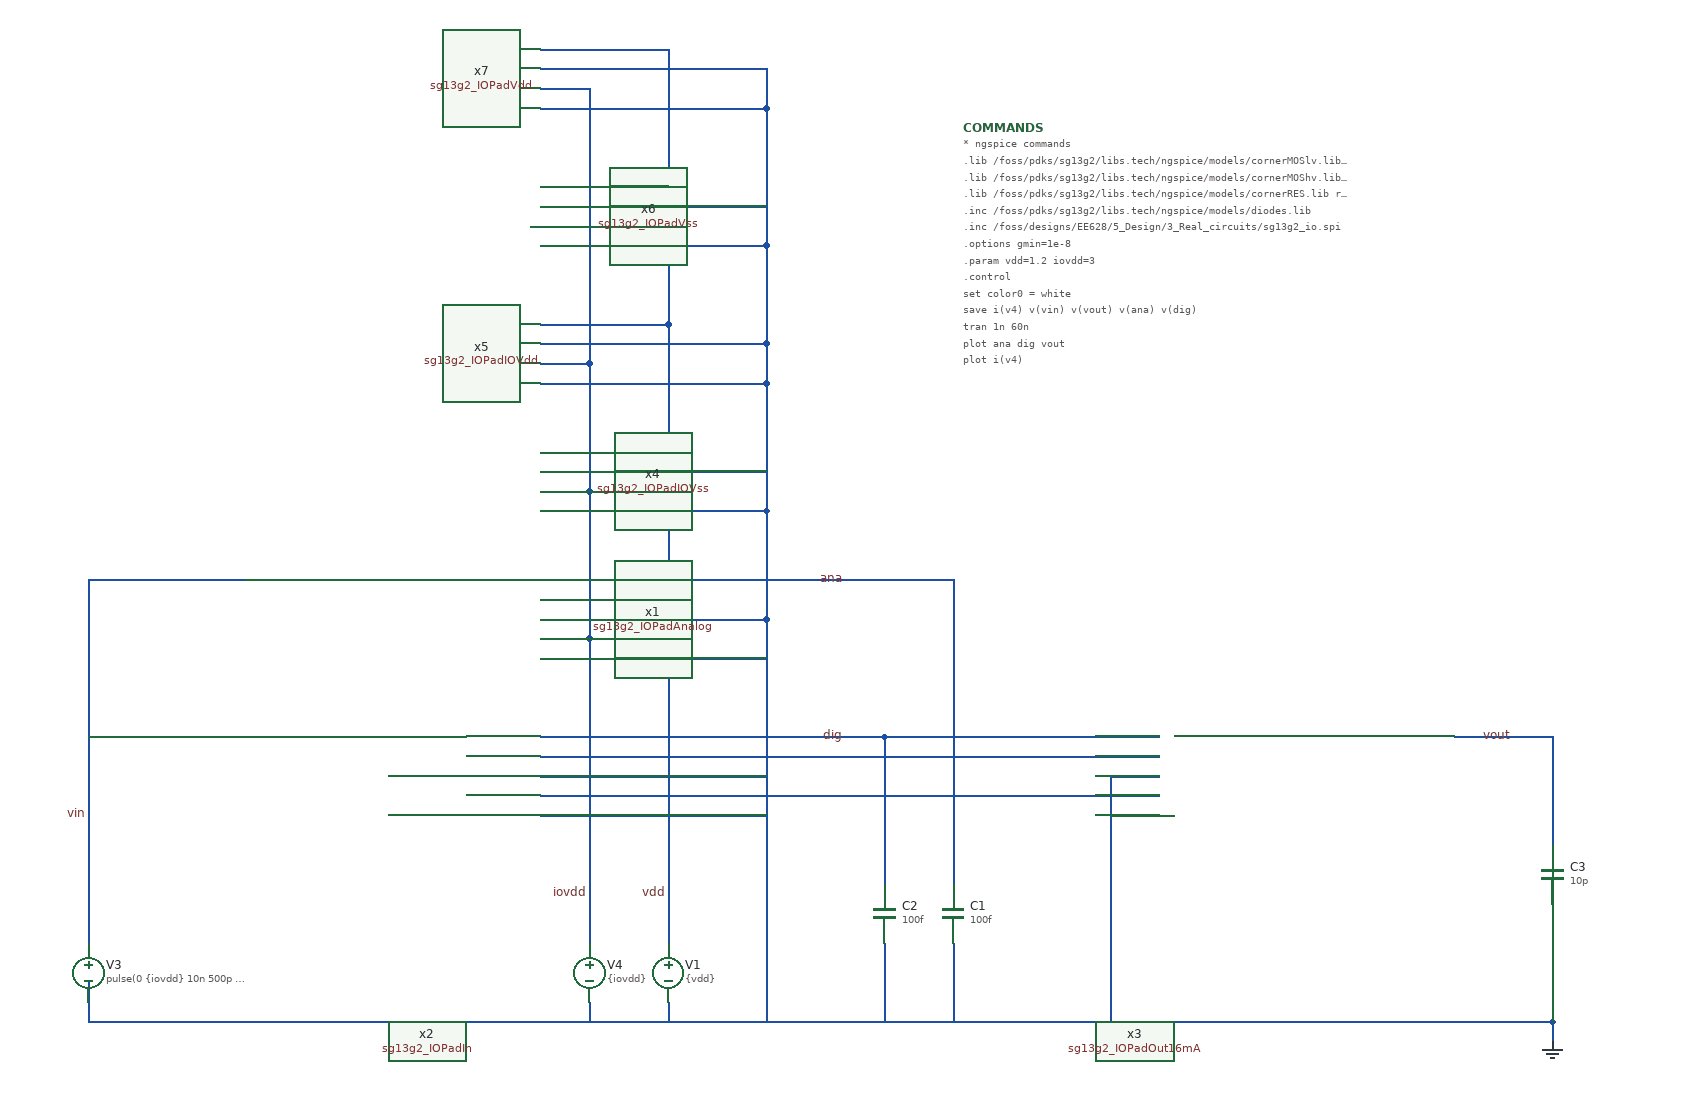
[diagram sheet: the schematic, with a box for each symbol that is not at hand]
v {xschem version=3.4.5 file_version=1.2
}
G {}
K {}
V {}
S {}
E {}
N 700 -630 760 -630 {
lab=GND}
N 700 -590 760 -590 {
lab=GND}
N 700 -470 760 -470 {
lab=GND}
N 700 -430 760 -430 {
lab=GND}
N 1560 -220 1560 -200 {
lab=GND}
N 660 -650 660 -340 {
lab=vdd}
N 760 -630 760 -340 {
lab=GND}
N 160 -670 210 -670 {
lab=vin}
N 160 -510 210 -510 {
lab=vin}
N 70 -550 70 -320 {
lab=vin}
N 700 -670 890 -670 {
lab=ana}
N 700 -510 880 -510 {
lab=dig}
N 1100 -510 1160 -510 {
lab=dig}
N 1110 -470 1160 -470 {
lab=GND}
N 1110 -430 1160 -430 {
lab=GND}
N 1060 -490 1160 -490 {
lab=vdd}
N 1060 -450 1160 -450 {
lab=iovdd}
N 1460 -510 1530 -510 {
lab=vout}
N 1530 -510 1560 -510 {
lab=vout}
N 1560 -510 1560 -480 {
lab=vout}
N 620 -670 700 -670 {
lab=ana}
N 620 -630 700 -630 {
lab=GND}
N 620 -590 700 -590 {
lab=GND}
N 620 -510 700 -510 {
lab=dig}
N 620 -470 700 -470 {
lab=GND}
N 620 -430 700 -430 {
lab=GND}
N 580 -370 580 -300 {
lab=iovdd}
N 580 -610 580 -370 {
lab=iovdd}
N 530 -610 580 -610 {
lab=iovdd}
N 530 -450 580 -450 {
lab=iovdd}
N 210 -670 230 -670 {
lab=vin}
N 210 -510 230 -510 {
lab=vin}
N 1000 -510 1100 -510 {
lab=dig}
N 580 -760 580 -610 {
lab=iovdd}
N 530 -760 580 -760 {
lab=iovdd}
N 760 -740 760 -630 {
lab=GND}
N 620 -740 760 -740 {
lab=GND}
N 530 -890 580 -890 {
lab=iovdd}
N 580 -890 580 -760 {
lab=iovdd}
N 760 -870 760 -740 {
lab=GND}
N 620 -780 760 -780 {
lab=GND}
N 660 -800 660 -650 {
lab=vdd}
N 660 -930 660 -800 {
lab=vdd}
N 760 -910 760 -870 {
lab=GND}
N 530 -1170 580 -1170 {
lab=iovdd}
N 580 -1170 580 -890 {
lab=iovdd}
N 520 -1030 580 -1030 {
lab=iovdd}
N 760 -1010 760 -910 {
lab=GND}
N 760 -1150 760 -1010 {
lab=GND}
N 660 -1210 660 -930 {
lab=vdd}
N 540 -1210 660 -1210 {
lab=vdd}
N 760 -1190 760 -1150 {
lab=GND}
N 70 -670 160 -670 {
lab=vin}
N 70 -670 70 -550 {
lab=vin}
N 70 -510 160 -510 {
lab=vin}
N 1560 -420 1560 -390 {
lab=vout}
N 160 -220 1560 -220 {
lab=GND}
N 70 -260 70 -220 {
lab=GND}
N 580 -240 580 -230 {
lab=GND}
N 580 -230 580 -220 {
lab=GND}
N 660 -240 660 -220 {
lab=GND}
N 70 -320 70 -300 {
lab=vin}
N 70 -260 70 -240 {
lab=GND}
N 1110 -420 1110 -220 {
lab=GND}
N 760 -340 760 -220 {
lab=GND}
N 880 -510 1000 -510 {
lab=dig}
N 1560 -480 1560 -420 {
lab=vout}
N 1560 -340 1560 -220 {
lab=GND}
N 1110 -470 1110 -420 {
lab=GND}
N 530 -670 620 -670 {
lab=ana}
N 530 -650 620 -650 {
lab=vdd}
N 530 -630 620 -630 {
lab=GND}
N 530 -590 620 -590 {
lab=GND}
N 530 -510 620 -510 {
lab=dig}
N 530 -470 620 -470 {
lab=GND}
N 530 -430 620 -430 {
lab=GND}
N 530 -800 620 -800 {
lab=vdd}
N 530 -780 620 -780 {
lab=GND}
N 530 -740 620 -740 {
lab=GND}
N 530 -930 620 -930 {
lab=vdd}
N 530 -910 620 -910 {
lab=GND}
N 530 -1050 620 -1050 {
lab=GND}
N 70 -220 160 -220 {
lab=GND}
N 660 -340 660 -300 {
lab=vdd}
N 610 -490 660 -490 {
lab=vdd}
N 530 -490 610 -490 {
lab=vdd}
N 880 -300 880 -220 {
lab=GND}
N 950 -300 950 -220 {
lab=GND}
N 880 -510 880 -360 {
lab=dig}
N 950 -650 950 -360 {
lab=ana}
N 890 -670 950 -670 {
lab=ana}
N 950 -670 950 -650 {
lab=ana}
N 620 -650 660 -650 {
lab=vdd}
N 660 -490 1060 -490 {
lab=vdd}
N 580 -450 1060 -450 {
lab=iovdd}
N 620 -800 660 -800 {
lab=vdd}
N 530 -870 760 -870 {
lab=GND}
N 620 -910 760 -910 {
lab=GND}
N 620 -930 660 -930 {
lab=vdd}
N 530 -1010 760 -1010 {
lab=GND}
N 620 -1050 760 -1050 {
lab=GND}
N 530 -1070 660 -1070 {
lab=vdd}
N 530 -1150 760 -1150 {
lab=GND}
N 530 -1190 760 -1190 {
lab=GND}
N 530 -1210 540 -1210 {
lab=vdd}
C {devices/title.sym} 160 -30 0 0 {name=l1 author="Boris Murmann"}
C {sg13g2_IOPadAnalog.sym} 380 -630 0 0 {name=x1}
C {sg13g2_IOPadIn.sym} 380 -470 0 0 {name=x2}
C {devices/vsource.sym} 660 -270 0 0 {name=V1 value=\{vdd\} savecurrent=false}
C {devices/gnd.sym} 1560 -200 0 0 {name=l3 lab=GND}
C {devices/vsource.sym} 70 -270 0 0 {name=V3 value="pulse(0 \{iovdd\} 10n 500p 500p 10n 20n)" savecurrent=false}
C {devices/lab_wire.sym} 70 -430 0 0 {name=p1 sig_type=std_logic lab=vin}
C {devices/lab_wire.sym} 660 -350 0 0 {name=p2 sig_type=std_logic lab=vdd}
C {devices/lab_wire.sym} 840 -670 0 0 {name=p4 sig_type=std_logic lab=ana}
C {devices/lab_wire.sym} 840 -510 0 0 {name=p5 sig_type=std_logic lab=dig}
C {devices/simulator_commands_shown.sym} 960 -1130 0 0 {name=COMMANDS
simulator=ngspice
only_toplevel=false 
value="
* ngspice commands
.lib /foss/pdks/sg13g2/libs.tech/ngspice/models/cornerMOSlv.lib mos_tt
.lib /foss/pdks/sg13g2/libs.tech/ngspice/models/cornerMOShv.lib mos_tt
.lib /foss/pdks/sg13g2/libs.tech/ngspice/models/cornerRES.lib res_typ
.inc /foss/pdks/sg13g2/libs.tech/ngspice/models/diodes.lib
.inc /foss/designs/EE628/5_Design/3_Real_circuits/sg13g2_io.spi
.options gmin=1e-8
.param vdd=1.2 iovdd=3

.control
set color0 = white
save i(v4) v(vin) v(vout) v(ana) v(dig)
tran 1n 60n
plot ana dig vout
plot i(v4)
.endc

"}
C {devices/capa.sym} 950 -330 0 0 {name=C1
m=1
value=100f
footprint=1206
device="ceramic capacitor"}
C {devices/capa.sym} 880 -330 0 0 {name=C2
m=1
value=100f
footprint=1206
device="ceramic capacitor"}
C {sg13g2_IOPadOut16mA.sym} 1310 -470 0 1 {name=x3}
C {devices/capa.sym} 1560 -370 0 0 {name=C3
m=1
value=10p
footprint=1206
device="ceramic capacitor"}
C {devices/lab_wire.sym} 1520 -510 0 0 {name=p6 sig_type=std_logic lab=vout}
C {devices/vsource.sym} 580 -270 0 0 {name=V4 value=\{iovdd\} savecurrent=false}
C {sg13g2_IOPadIOVss.sym} 380 -780 0 0 {name=x4}
C {sg13g2_IOPadIOVdd.sym} 380 -910 0 0 {name=x5}
C {sg13g2_IOPadVss.sym} 380 -1050 0 0 {name=x6}
C {sg13g2_IOPadVdd.sym} 380 -1190 0 0 {name=x7}
C {devices/lab_wire.sym} 580 -350 0 0 {name=p3 sig_type=std_logic lab=iovdd}
